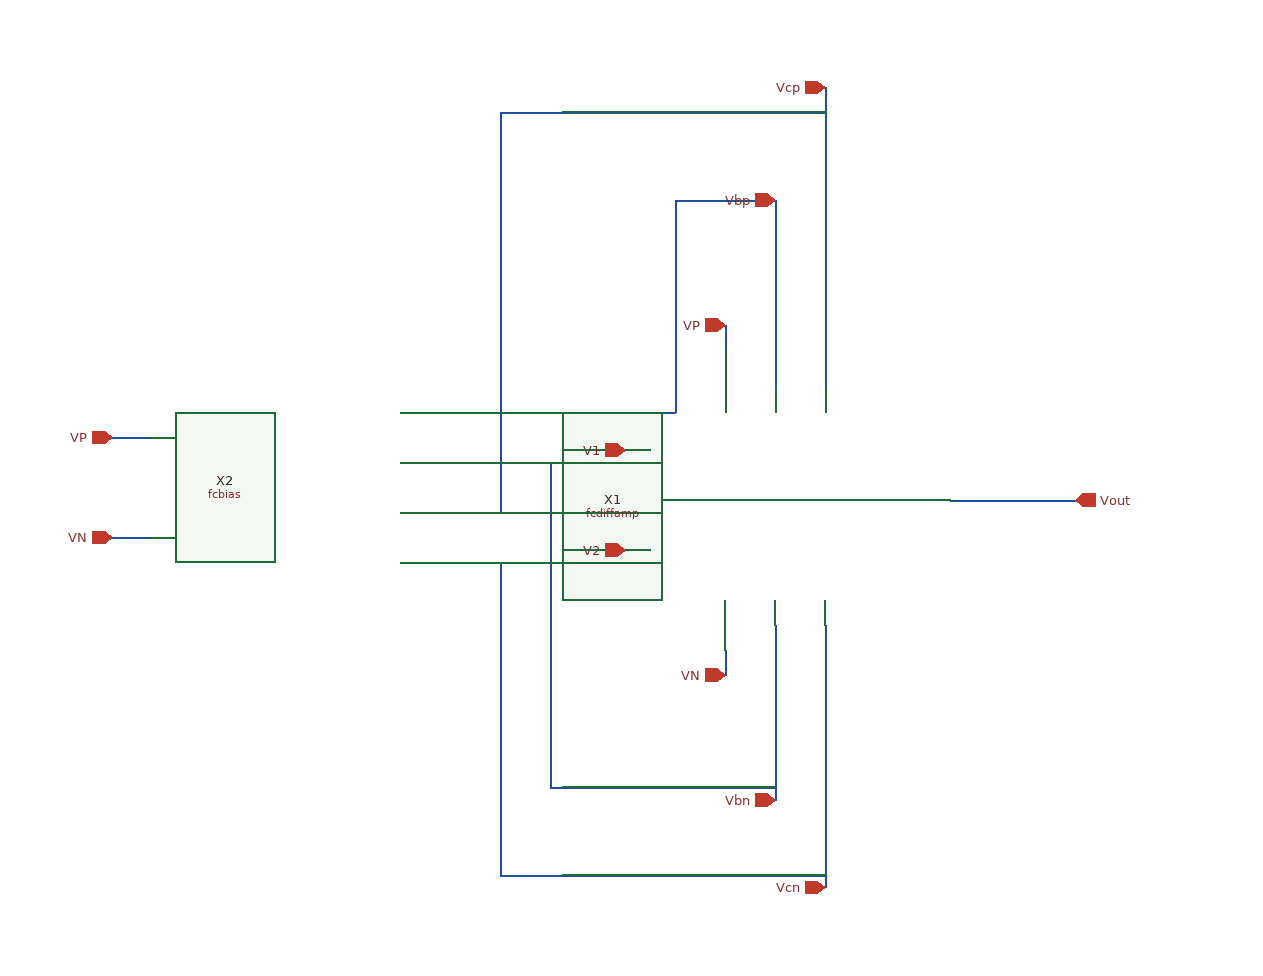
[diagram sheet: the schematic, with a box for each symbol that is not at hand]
v {xschem version=2.9.9 file_version=1.2 }
G {}
K {}
V {}
S {}
E {}
N 580 -370 580 -350 { lab=VN}
N 580 -630 580 -610 { lab=VP}
N 760 -490 860 -490 { lab=Vout}
N 90 -540 120 -540 { lab=VP}
N 90 -460 120 -460 { lab=VN}
N 320 -560 360 -560 { lab=Vbp}
N 320 -520 360 -520 { lab=Vbn}
N 320 -480 360 -480 { lab=Vcp}
N 320 -440 360 -440 { lab=Vcn}
N 620 -600 620 -580 { lab=Vbp}
N 660 -600 660 -580 { lab=Vcp}
N 500 -530 520 -530 { lab=V1}
N 500 -450 520 -450 { lab=V2}
N 620 -390 620 -370 { lab=Vbn}
N 660 -390 660 -370 { lab=Vcn}
N 620 -670 620 -600 { lab=Vbp}
N 360 -560 540 -560 { lab=Vbp}
N 540 -670 540 -560 { lab=Vbp}
N 540 -730 620 -730 { lab=Vbp}
N 360 -520 440 -520 { lab=Vbn}
N 440 -520 440 -300 { lab=Vbn}
N 440 -260 620 -260 { lab=Vbn}
N 620 -360 620 -300 { lab=Vbn}
N 620 -370 620 -360 { lab=Vbn}
N 620 -300 620 -290 { lab=Vbn}
N 360 -440 400 -440 { lab=Vcn}
N 400 -440 400 -230 { lab=Vcn}
N 400 -190 660 -190 { lab=Vcn}
N 660 -230 660 -220 { lab=Vcn}
N 660 -360 660 -230 { lab=Vcn}
N 660 -370 660 -360 { lab=Vcn}
N 360 -480 400 -480 { lab=Vcp}
N 400 -740 400 -480 { lab=Vcp}
N 400 -800 660 -800 { lab=Vcp}
N 660 -760 660 -600 { lab=Vcp}
N 400 -790 400 -740 { lab=Vcp}
N 660 -820 660 -760 { lab=Vcp}
N 540 -730 540 -670 { lab=Vbp}
N 620 -730 620 -670 { lab=Vbp}
N 400 -230 400 -190 { lab=Vcn}
N 440 -300 440 -260 { lab=Vbn}
N 620 -290 620 -250 { lab=Vbn}
N 660 -220 660 -180 { lab=Vcn}
N 400 -800 400 -790 { lab=Vcp}
C {/home/madvlsi/Documents/Miniproject3/fcdiffamp.sym} 460 -350 0 0 {name=X1}
C {/home/madvlsi/Documents/Miniproject3/fcbias.sym} 100 -360 0 0 {name=X2}
C {devices/iopin.sym} 660 -180 1 0 {name=p2 lab=Vcn}
C {devices/iopin.sym} 620 -250 1 0 {name=p4 lab=Vbn}
C {devices/ipin.sym} 500 -530 0 0 {name=p7 lab=V1}
C {devices/ipin.sym} 500 -450 0 0 {name=p8 lab=V2}
C {devices/opin.sym} 860 -490 0 0 {name=p9 lab=Vout}
C {devices/iopin.sym} 620 -730 3 0 {name=p10 lab=Vbp}
C {devices/iopin.sym} 660 -820 3 0 {name=p13 lab=Vcp}
C {devices/iopin.sym} 580 -630 3 0 {name=p1 lab=VP}
C {devices/iopin.sym} 90 -540 3 0 {name=p3 lab=VP}
C {devices/iopin.sym} 90 -460 1 0 {name=p5 lab=VN}
C {devices/iopin.sym} 580 -350 1 0 {name=p6 lab=VN}
